###############################################################
#  Generated by:      Cadence Innovus 23.15-s106_1
#  OS:                Linux x86_64(Host ID silo-rhel.luddy.indiana.edu)
#  Generated on:      Wed Sep 17 13:26:19 2025
#  Design:            sram_8_1024_sky130A
#  Command:           write_lef_abstract sram.lef
###############################################################

VERSION 5.8 ;

BUSBITCHARS "[]" ;
DIVIDERCHAR "/" ;

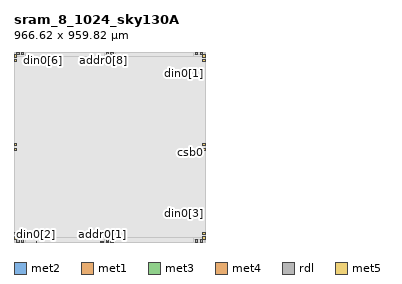
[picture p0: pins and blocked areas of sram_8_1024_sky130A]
MACRO sram_8_1024_sky130A
  CLASS BLOCK ;
  SIZE 966.620000 BY 959.820000 ;
  FOREIGN sram_8_1024_sky130A 0.000000 0.000000 ;
  ORIGIN 0 0 ;
  SYMMETRY X Y R90 ;
  PIN clk
    DIRECTION INPUT ;
    USE SIGNAL ;
    PORT
      LAYER met2 ;
        RECT 489.360000 0.000000 489.500000 0.485000 ;
    END
  END clk
  PIN csb0
    DIRECTION INPUT ;
    USE SIGNAL ;
    PORT
      LAYER met1 ;
        RECT 966.025000 450.260000 966.620000 450.400000 ;
    END
  END csb0
  PIN web0
    DIRECTION INPUT ;
    USE SIGNAL ;
    PORT
      LAYER met3 ;
        RECT 965.820000 450.410000 966.620000 450.710000 ;
    END
  END web0
  PIN addr0[9]
    DIRECTION INPUT ;
    USE SIGNAL ;
    PORT
      LAYER met2 ;
        RECT 474.740000 0.000000 474.880000 0.485000 ;
    END
  END addr0[9]
  PIN addr0[8]
    DIRECTION INPUT ;
    USE SIGNAL ;
    PORT
      LAYER met2 ;
        RECT 453.660000 959.335000 453.800000 959.820000 ;
    END
  END addr0[8]
  PIN addr0[7]
    DIRECTION INPUT ;
    USE SIGNAL ;
    PORT
      LAYER met2 ;
        RECT 475.420000 0.000000 475.560000 0.485000 ;
    END
  END addr0[7]
  PIN addr0[6]
    DIRECTION INPUT ;
    USE SIGNAL ;
    PORT
      LAYER met1 ;
        RECT 966.025000 460.460000 966.620000 460.600000 ;
    END
  END addr0[6]
  PIN addr0[5]
    DIRECTION INPUT ;
    USE SIGNAL ;
    PORT
      LAYER met2 ;
        RECT 465.220000 0.000000 465.360000 0.485000 ;
    END
  END addr0[5]
  PIN addr0[4]
    DIRECTION INPUT ;
    USE SIGNAL ;
    PORT
      LAYER met2 ;
        RECT 454.000000 0.000000 454.140000 0.485000 ;
    END
  END addr0[4]
  PIN addr0[3]
    DIRECTION INPUT ;
    USE SIGNAL ;
    PORT
      LAYER met2 ;
        RECT 440.400000 0.000000 440.540000 0.485000 ;
    END
  END addr0[3]
  PIN addr0[2]
    DIRECTION INPUT ;
    USE SIGNAL ;
    PORT
      LAYER met2 ;
        RECT 437.000000 0.000000 437.140000 0.485000 ;
    END
  END addr0[2]
  PIN addr0[1]
    DIRECTION INPUT ;
    USE SIGNAL ;
    PORT
      LAYER met2 ;
        RECT 445.160000 0.000000 445.300000 0.485000 ;
    END
  END addr0[1]
  PIN addr0[0]
    DIRECTION INPUT ;
    USE SIGNAL ;
    PORT
      LAYER met4 ;
        RECT 445.420000 0.000000 445.720000 0.800000 ;
    END
  END addr0[0]
  PIN din0[7]
    DIRECTION INPUT ;
    USE SIGNAL ;
    PORT
      LAYER met2 ;
        RECT 112.300000 0.000000 112.440000 0.485000 ;
    END
  END din0[7]
  PIN din0[6]
    DIRECTION INPUT ;
    USE SIGNAL ;
    PORT
      LAYER met2 ;
        RECT 144.260000 959.335000 144.400000 959.820000 ;
    END
  END din0[6]
  PIN din0[5]
    DIRECTION INPUT ;
    USE SIGNAL ;
    PORT
      LAYER met1 ;
        RECT 966.025000 858.940000 966.620000 859.080000 ;
    END
  END din0[5]
  PIN din0[4]
    DIRECTION INPUT ;
    USE SIGNAL ;
    PORT
      LAYER met1 ;
        RECT 966.025000 863.360000 966.620000 863.500000 ;
    END
  END din0[4]
  PIN din0[3]
    DIRECTION INPUT ;
    USE SIGNAL ;
    PORT
      LAYER met1 ;
        RECT 966.025000 143.920000 966.620000 144.060000 ;
    END
  END din0[3]
  PIN din0[2]
    DIRECTION INPUT ;
    USE SIGNAL ;
    PORT
      LAYER met2 ;
        RECT 111.280000 0.000000 111.420000 0.485000 ;
    END
  END din0[2]
  PIN din0[1]
    DIRECTION INPUT ;
    USE SIGNAL ;
    PORT
      LAYER met1 ;
        RECT 966.025000 852.140000 966.620000 852.280000 ;
    END
  END din0[1]
  PIN din0[0]
    DIRECTION INPUT ;
    USE SIGNAL ;
    PORT
      LAYER met3 ;
        RECT 965.820000 144.190000 966.620000 144.490000 ;
    END
  END din0[0]
  PIN dout0[7]
    DIRECTION OUTPUT ;
    USE SIGNAL ;
    PORT
      LAYER met1 ;
        RECT 966.025000 467.600000 966.620000 467.740000 ;
    END
  END dout0[7]
  PIN dout0[6]
    DIRECTION OUTPUT ;
    USE SIGNAL ;
    PORT
      LAYER met1 ;
        RECT 966.025000 465.220000 966.620000 465.360000 ;
    END
  END dout0[6]
  PIN dout0[5]
    DIRECTION OUTPUT ;
    USE SIGNAL ;
    PORT
      LAYER met1 ;
        RECT 966.025000 454.340000 966.620000 454.480000 ;
    END
  END dout0[5]
  PIN dout0[4]
    DIRECTION OUTPUT ;
    USE SIGNAL ;
    PORT
      LAYER met3 ;
        RECT 965.820000 454.070000 966.620000 454.370000 ;
    END
  END dout0[4]
  PIN dout0[3]
    DIRECTION OUTPUT ;
    USE SIGNAL ;
    PORT
      LAYER met1 ;
        RECT 966.025000 469.300000 966.620000 469.440000 ;
    END
  END dout0[3]
  PIN dout0[2]
    DIRECTION OUTPUT ;
    USE SIGNAL ;
    PORT
      LAYER met1 ;
        RECT 966.025000 453.660000 966.620000 453.800000 ;
    END
  END dout0[2]
  PIN dout0[1]
    DIRECTION OUTPUT ;
    USE SIGNAL ;
    PORT
      LAYER met3 ;
        RECT 965.820000 465.050000 966.620000 465.350000 ;
    END
  END dout0[1]
  PIN dout0[0]
    DIRECTION OUTPUT ;
    USE SIGNAL ;
    PORT
      LAYER met1 ;
        RECT 966.025000 470.660000 966.620000 470.800000 ;
    END
  END dout0[0]
  PIN VPWR
    DIRECTION INOUT ;
    USE POWER ;
    PORT
      LAYER rdl ;
        RECT 14.040000 0.000000 26.040000 12.000000 ;
    END
    PORT
      LAYER rdl ;
        RECT 14.040000 947.820000 26.040000 959.820000 ;
    END
    PORT
      LAYER rdl ;
        RECT 465.310000 0.000000 477.310000 12.000000 ;
    END
    PORT
      LAYER rdl ;
        RECT 465.310000 947.820000 477.310000 959.820000 ;
    END
    PORT
      LAYER rdl ;
        RECT 916.580000 0.000000 928.580000 12.000000 ;
    END
    PORT
      LAYER rdl ;
        RECT 916.580000 947.820000 928.580000 959.820000 ;
    END
    PORT
      LAYER met5 ;
        RECT 0.000000 14.040000 12.000000 26.040000 ;
    END
    PORT
      LAYER met5 ;
        RECT 954.620000 14.040000 966.620000 26.040000 ;
    END
    PORT
      LAYER met5 ;
        RECT 0.000000 461.895000 12.000000 473.895000 ;
    END
    PORT
      LAYER met5 ;
        RECT 954.620000 461.895000 966.620000 473.895000 ;
    END
    PORT
      LAYER met5 ;
        RECT 0.000000 909.750000 12.000000 921.750000 ;
    END
    PORT
      LAYER met5 ;
        RECT 954.620000 909.750000 966.620000 921.750000 ;
    END
  END VPWR
  PIN VGND
    DIRECTION INOUT ;
    USE GROUND ;
    PORT
      LAYER rdl ;
        RECT 38.040000 0.000000 50.040000 12.000000 ;
    END
    PORT
      LAYER rdl ;
        RECT 38.040000 947.820000 50.040000 959.820000 ;
    END
    PORT
      LAYER rdl ;
        RECT 489.310000 0.000000 501.310000 12.000000 ;
    END
    PORT
      LAYER rdl ;
        RECT 489.310000 947.820000 501.310000 959.820000 ;
    END
    PORT
      LAYER rdl ;
        RECT 940.580000 0.000000 952.580000 12.000000 ;
    END
    PORT
      LAYER rdl ;
        RECT 940.580000 947.820000 952.580000 959.820000 ;
    END
    PORT
      LAYER met5 ;
        RECT 0.000000 38.040000 12.000000 50.040000 ;
    END
    PORT
      LAYER met5 ;
        RECT 954.620000 38.040000 966.620000 50.040000 ;
    END
    PORT
      LAYER met5 ;
        RECT 0.000000 485.895000 12.000000 497.895000 ;
    END
    PORT
      LAYER met5 ;
        RECT 954.620000 485.895000 966.620000 497.895000 ;
    END
    PORT
      LAYER met5 ;
        RECT 0.000000 933.750000 12.000000 945.750000 ;
    END
    PORT
      LAYER met5 ;
        RECT 954.620000 933.750000 966.620000 945.750000 ;
    END
  END VGND
  OBS
    LAYER li1 ;
      RECT 0.000000 0.000000 966.620000 959.820000 ;
    LAYER met1 ;
      RECT 0.000000 863.640000 966.620000 959.820000 ;
      RECT 0.000000 863.220000 965.885000 863.640000 ;
      RECT 0.000000 859.220000 966.620000 863.220000 ;
      RECT 0.000000 858.800000 965.885000 859.220000 ;
      RECT 0.000000 852.420000 966.620000 858.800000 ;
      RECT 0.000000 852.000000 965.885000 852.420000 ;
      RECT 0.000000 470.940000 966.620000 852.000000 ;
      RECT 0.000000 470.520000 965.885000 470.940000 ;
      RECT 0.000000 469.580000 966.620000 470.520000 ;
      RECT 0.000000 469.160000 965.885000 469.580000 ;
      RECT 0.000000 467.880000 966.620000 469.160000 ;
      RECT 0.000000 467.460000 965.885000 467.880000 ;
      RECT 0.000000 465.500000 966.620000 467.460000 ;
      RECT 0.000000 465.080000 965.885000 465.500000 ;
      RECT 0.000000 460.740000 966.620000 465.080000 ;
      RECT 0.000000 460.320000 965.885000 460.740000 ;
      RECT 0.000000 454.620000 966.620000 460.320000 ;
      RECT 0.000000 454.200000 965.885000 454.620000 ;
      RECT 0.000000 453.940000 966.620000 454.200000 ;
      RECT 0.000000 453.520000 965.885000 453.940000 ;
      RECT 0.000000 450.540000 966.620000 453.520000 ;
      RECT 0.000000 450.120000 965.885000 450.540000 ;
      RECT 0.000000 144.200000 966.620000 450.120000 ;
      RECT 0.000000 143.780000 965.885000 144.200000 ;
      RECT 0.000000 0.000000 966.620000 143.780000 ;
    LAYER met2 ;
      RECT 453.940000 959.195000 966.620000 959.820000 ;
      RECT 144.540000 959.195000 453.520000 959.820000 ;
      RECT 0.000000 959.195000 144.120000 959.820000 ;
      RECT 0.000000 0.625000 966.620000 959.195000 ;
      RECT 489.640000 0.000000 966.620000 0.625000 ;
      RECT 475.700000 0.000000 489.220000 0.625000 ;
      RECT 475.020000 0.000000 475.280000 0.625000 ;
      RECT 465.500000 0.000000 474.600000 0.625000 ;
      RECT 454.280000 0.000000 465.080000 0.625000 ;
      RECT 445.440000 0.000000 453.860000 0.625000 ;
      RECT 440.680000 0.000000 445.020000 0.625000 ;
      RECT 437.280000 0.000000 440.260000 0.625000 ;
      RECT 112.580000 0.000000 436.860000 0.625000 ;
      RECT 111.560000 0.000000 112.160000 0.625000 ;
      RECT 0.000000 0.000000 111.140000 0.625000 ;
    LAYER met3 ;
      RECT 0.000000 465.650000 966.620000 959.820000 ;
      RECT 0.000000 464.750000 965.520000 465.650000 ;
      RECT 0.000000 454.670000 966.620000 464.750000 ;
      RECT 0.000000 453.770000 965.520000 454.670000 ;
      RECT 0.000000 451.010000 966.620000 453.770000 ;
      RECT 0.000000 450.110000 965.520000 451.010000 ;
      RECT 0.000000 144.790000 966.620000 450.110000 ;
      RECT 0.000000 143.890000 965.520000 144.790000 ;
      RECT 0.000000 0.000000 966.620000 143.890000 ;
    LAYER met4 ;
      RECT 0.000000 1.100000 966.620000 959.820000 ;
      RECT 446.020000 0.000000 966.620000 1.100000 ;
      RECT 0.000000 0.000000 445.120000 1.100000 ;
    LAYER met5 ;
      RECT 0.000000 947.350000 966.620000 959.820000 ;
      RECT 13.600000 932.150000 953.020000 947.350000 ;
      RECT 0.000000 923.350000 966.620000 932.150000 ;
      RECT 13.600000 908.150000 953.020000 923.350000 ;
      RECT 0.000000 499.495000 966.620000 908.150000 ;
      RECT 13.600000 484.295000 953.020000 499.495000 ;
      RECT 0.000000 475.495000 966.620000 484.295000 ;
      RECT 13.600000 460.295000 953.020000 475.495000 ;
      RECT 0.000000 51.640000 966.620000 460.295000 ;
      RECT 13.600000 36.440000 953.020000 51.640000 ;
      RECT 0.000000 27.640000 966.620000 36.440000 ;
      RECT 13.600000 12.440000 953.020000 27.640000 ;
      RECT 0.000000 0.000000 966.620000 12.440000 ;
    LAYER rdl ;
      RECT 962.580000 937.820000 966.620000 959.820000 ;
      RECT 511.310000 937.820000 906.580000 959.820000 ;
      RECT 60.040000 937.820000 455.310000 959.820000 ;
      RECT 0.000000 937.820000 4.040000 959.820000 ;
      RECT 0.000000 22.000000 966.620000 937.820000 ;
      RECT 962.580000 0.000000 966.620000 22.000000 ;
      RECT 511.310000 0.000000 906.580000 22.000000 ;
      RECT 60.040000 0.000000 455.310000 22.000000 ;
      RECT 0.000000 0.000000 4.040000 22.000000 ;
  END
END sram_8_1024_sky130A

END LIBRARY
